One B-rep face of a CAD part: STEP entity #291.
In plain terms, the planar face has unit normal (1, 0, 0).
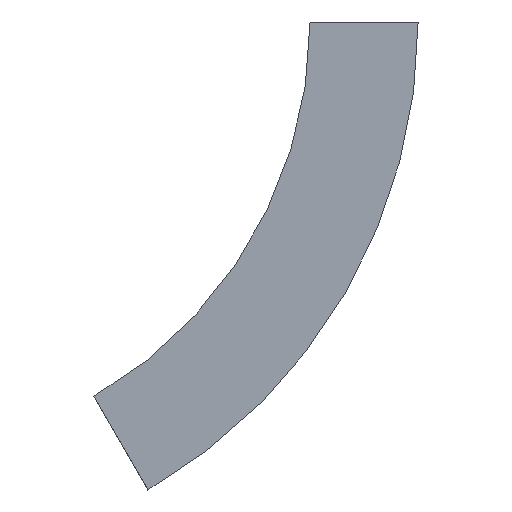
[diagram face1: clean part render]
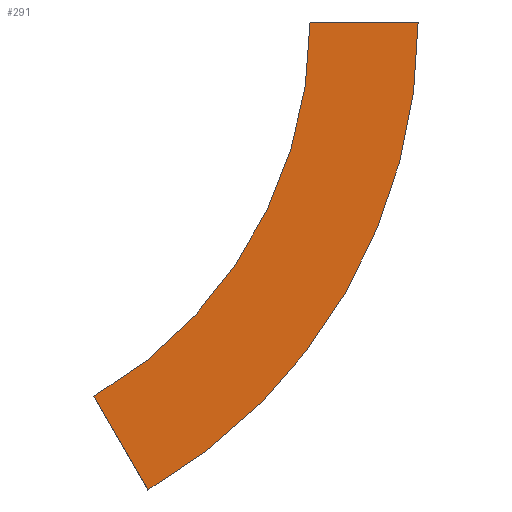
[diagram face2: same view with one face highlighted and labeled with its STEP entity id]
Its self-contained STEP definition (entity closure, numbers rounded to 3 decimals):
#4 = EDGE_LOOP ( 'NONE', ( #55, #509, #287, #374 ) ) ;
#15 = CARTESIAN_POINT ( 'NONE',  ( 0., -75., 0. ) ) ;
#16 = VERTEX_POINT ( 'NONE', #189 ) ;
#30 = VERTEX_POINT ( 'NONE', #313 ) ;
#54 = PLANE ( 'NONE',  #529 ) ;
#55 = ORIENTED_EDGE ( 'NONE', *, *, #561, .F. ) ;
#86 = DIRECTION ( 'NONE',  ( 0., -1., 0. ) ) ;
#116 = CARTESIAN_POINT ( 'NONE',  ( 0., 300., 0. ) ) ;
#145 = CIRCLE ( 'NONE', #220, 300. ) ;
#146 = VERTEX_POINT ( 'NONE', #432 ) ;
#168 = LINE ( 'NONE', #175, #526 ) ;
#175 = CARTESIAN_POINT ( 'NONE',  ( 0., -75., 0. ) ) ;
#182 = EDGE_CURVE ( 'NONE', #30, #16, #215, .T. ) ;
#189 = CARTESIAN_POINT ( 'NONE',  ( 0., 150., -259.808 ) ) ;
#202 = VERTEX_POINT ( 'NONE', #485 ) ;
#215 = LINE ( 'NONE', #484, #571 ) ;
#220 = AXIS2_PLACEMENT_3D ( 'NONE', #268, #537, #86 ) ;
#260 = DIRECTION ( 'NONE',  ( 1., 0., 0. ) ) ;
#268 = CARTESIAN_POINT ( 'NONE',  ( 0., 300., 0. ) ) ;
#287 = ORIENTED_EDGE ( 'NONE', *, *, #418, .T. ) ;
#291 = ADVANCED_FACE ( 'NONE', ( #459 ), #54, .F. ) ;
#308 = DIRECTION ( 'NONE',  ( 0., 0.5, 0.866 ) ) ;
#312 = DIRECTION ( 'NONE',  ( 0., 1., 0. ) ) ;
#313 = CARTESIAN_POINT ( 'NONE',  ( 0., 112.5, -324.76 ) ) ;
#371 = DIRECTION ( 'NONE',  ( -1., 0., 0. ) ) ;
#374 = ORIENTED_EDGE ( 'NONE', *, *, #182, .T. ) ;
#403 = DIRECTION ( 'NONE',  ( 0., 0., 1. ) ) ;
#418 = EDGE_CURVE ( 'NONE', #202, #30, #567, .T. ) ;
#432 = CARTESIAN_POINT ( 'NONE',  ( 0., 0., 0. ) ) ;
#433 = AXIS2_PLACEMENT_3D ( 'NONE', #116, #260, #435 ) ;
#435 = DIRECTION ( 'NONE',  ( 0., -1., 0. ) ) ;
#459 = FACE_OUTER_BOUND ( 'NONE', #4, .T. ) ;
#484 = CARTESIAN_POINT ( 'NONE',  ( 0., 112.5, -324.76 ) ) ;
#485 = CARTESIAN_POINT ( 'NONE',  ( 0., -75., 0. ) ) ;
#509 = ORIENTED_EDGE ( 'NONE', *, *, #564, .F. ) ;
#526 = VECTOR ( 'NONE', #312, 1000. ) ;
#529 = AXIS2_PLACEMENT_3D ( 'NONE', #15, #371, #403 ) ;
#537 = DIRECTION ( 'NONE',  ( 1., 0., 0. ) ) ;
#561 = EDGE_CURVE ( 'NONE', #146, #16, #145, .T. ) ;
#564 = EDGE_CURVE ( 'NONE', #202, #146, #168, .T. ) ;
#567 = CIRCLE ( 'NONE', #433, 375. ) ;
#571 = VECTOR ( 'NONE', #308, 1000. ) ;
